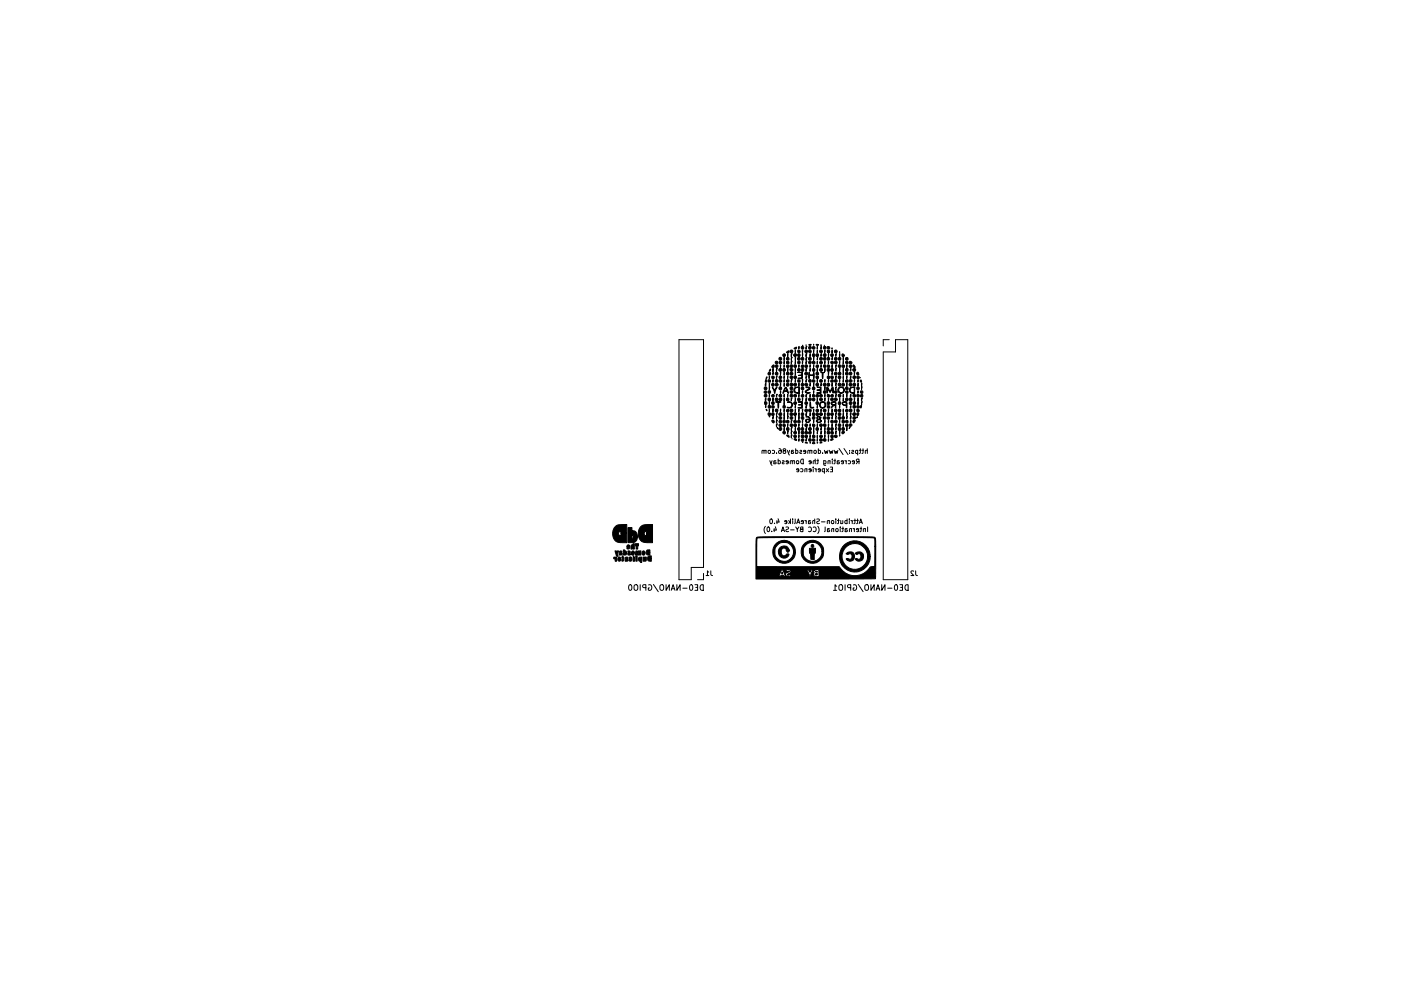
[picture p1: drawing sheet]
<svg xmlns="http://www.w3.org/2000/svg" width="297mm" height="210mm" viewBox="0 0 297 210" stroke-linecap="round" stroke-linejoin="round" font-family="sans-serif">
<g fill="none" stroke="#000" stroke-width=".21">
<path d="M144 72.1h5.2v48.3h-2.6v2.6h-2.6zM188.5 72.1h-1.2v1.3M189.9 72.1h2.6v50.9h-5.2v-48.3h2.6zM162 95.7l-.4-.1v.6M162.4 95.6h-.4v.6M162.4 95.5v.7M162.9 95.6h.4v.6l-.4-.1zM163.2 97.7l.5 1M163.7 97.7l-.2 .7M163.7 95.6l.3-.1 .2 .2-.1 .5h-.4M164.5 97.8l-.3-.1-.1 .2v.5h.3l.1-.3-.4-.1M164.6 96.1v.1"/>
<path d="M165 97.4v1h.4v-.6h-.4M165.2 95.2l.4 .2v.6l-.1 .2-.4-.1 .1-.5h.3l.1 .2M165.9 97.8l.4 .1-.4 .2v.3h.4M166.2 95.6l-.2 .2 .2 .4 .4-.1v-.3l-.5-.3v-.2h.5l-.2 .3M166.9 95.5l.5 1M167.1 98.1l-.5-.1 .1-.2 .3-.1 .1 .2v.5h-.4M167.4 95.5l-.2 .7M167.8 95.8l.5 .2-.2 .2h-.3M168 97.9l-.4-.1v.6M168.2 95.6h-.4v.6M168.4 97.8h-.4v.6M168.4 97.7v.7"/>
<path d="M168.7 95.6l.3-.1 .2 .2-.1 .5h-.4M168.7 95.2v1M168.9 97.8h.4v.6l-.4-.1zM169.4 99.8l-.5-.1v-.2l.3-.1 .2 .2-.1 .5h-.4M169.6 95.6l.4 .1-.4 .2v.3h.4M169.7 99.5l.3-.1 .2 .2-.1 .5h-.4M169.8 97.5l.5-.1v1a.52 .52 0 0 1-.5-.3 .52 .52 0 0 1 0-.6zM170.8 95.9l-.4-.1v-.2l.3-.1 .1 .2v.5h-.4M171.1 99.5h-.4l-.1 .6M171.1 99.4v.7M171.7 95.7l-.4-.1v.6M172 98.1l-.5-.1 .1-.2 .2-.1 .2 .2-.1 .5h-.3"/>
<path d="M172 99.8l-.5-.1 .1-.2 .2-.1 .2 .2-.1 .5h-.3M172.1 95.6h-.4v.6M172.1 95.5v.7M172.4 99.1v.1M172.4 99.4v.7M172.6 95.6h.4v.6l-.4-.1zM172.7 99.4l.3 .2M172.8 97.8h-.3l-.1 .6M172.8 97.4v1M173 99.4v.7M173.2 97.7h.4M173.4 97.4v.9l-.2 .1"/>
<path d="M173.5 95.6l.3-.1 .2 .2-.1 .5h-.4M173.5 95.2v1M173.9 99.8l-.4-.1v-.2l.3-.1 .1 .2v.5h-.4M174.4 96.1v.1M174.6 97.7v.8l.2 .2h.3M174.6 97.8l.3-.1 .2 .2-.1 .5h-.4M174.8 99.5l-.3-.1-.2 .2 .1 .5h.4M174.8 95.5l.2 .7 .2-.5 .2 .5 .2-.7M174.8 99.4v1M175.2 99.4l.5 .7M175.7 99.4l-.5 .7M175.8 95.5l.2 .7 .2-.5 .2 .5 .2-.7"/>
<path d="M176 97.8h-.4v.6M176 97.7v.7M176 99.1h.5v1h-.5M176.2 99.6h.3M176.5 97.4v.1M176.5 97.7v.7M176.8 97.7h.4M176.9 95.5l.2 .7 .2-.5 .2 .5 .1-.7M177 97.4v.9l-.2 .1M177.9 95.2l.8 1.2M177.9 97.8l-.3-.1-.1 .2v.5h.3l.1-.3-.4-.1M178.8 98.1l-.4-.1v-.2l.3-.1 .1 .2v.5h-.4"/>
<path d="M178.9 95.2l.9 1.2M179.1 97.7l.3 .2M179.4 97.7v.7M179.8 97.8l.3-.1 .2 .2-.1 .5h-.4M180.1 96.1v.1M180.1 95.6v.1M180.6 95.6l.4 .1-.4 .2v.3h.4M181.2 98.1l-.5-.1v-.2l.3-.1 .2 .2-.1 .5h-.4M181.8 95.6l-.2-.1-.2 .2 .1 .5h.3M181.8 95.5v1M181.9 97.9l-.3 .5M182.1 97.9h-.5v-.4l.5-.1v1"/>
<path d="M182.2 95.5h.4M182.4 95.2v.9l-.2 .1M182.7 95.5h.4M183 95.2v.9l-.3 .1M183.9 95.6h-.4v.6M183.9 95.2v1M162.3 111.7a1.15 1.15 0 0 0 0 1.5M162.7 111.9l.2-.1a.49 .49 0 0 1 .3 .5 .49 .49 0 0 1-.4 .5l-.2-.4zM163.4 110.2l.1-.1a.49 .49 0 0 1 .3 .5 .49 .49 0 0 1-.4 .5l-.2-.4zM163.6 112.7v.1M164.1 112.1v.7M164.2 111v.1"/>
<path d="M164.4 111.8l.2 .7h-.6M164.7 110.4v.7M165 110.1l.2 .7h-.6M165.7 112.8l.3-1 .3 1M165.8 112.5h.4M166.6 111.9h.5a.42 .42 0 0 1-.4 .5v.4h.5M166.8 110.8l-.4-.1v-.2l.3-.1 .1 .2v.5h-.4M167.2 110.4l.4 .4M167.5 110.7l-.3 .4M167.6 110.1v1M167.6 112.4h.8M168.1 110.1v.1"/>
<path d="M168.1 110.4v.7M168.6 110.1v.9l-.1 .1M168.7 111.8l.3 .5 .4-.5M168.9 111.1l.4-1 .3 1M169 110.8h.5M169 112.3v.5M169.9 112.3l-.2 .2 .2 .3h.3v-1l-.4 .1v.3l.4 .1M170.4 110.8l-.5-.1v-.2l.3-.1 .2 .2-.1 .5h-.4M170.6 110.4l.3 .2M170.9 110.4v.7M171.4 110.7l.5 .2-.2 .2h-.3M171.4 111.9a.44 .44 0 0 1 .7 .4 .44 .44 0 0 1-.7 .4"/>
<path d="M171.8 110.5h-.3l-.1 .6M172.4 111.9a.44 .44 0 0 1 .7 .4 .44 .44 0 0 1-.7 .4M172.7 110.5h-.3l-.1 .6M172.7 110.1v1M173.2 110.2h.5a.42 .42 0 0 1-.5 .5l.1 .4h.4M173.4 111.7a1.15 1.15 0 0 1 0 1.5M174.2 110.7h.7M175 111.8v.9l-.2 .1M175.4 112.4l.5 .2-.1 .2h-.4M175.8 110.5h-.3l-.1 .6M175.8 110.4v.7M175.9 112.2h-.4l-.1 .6"/>
<path d="M176.3 110.5h.4v.6l-.4-.1zM176.8 112.2h-.4l-.1 .6M176.8 112.1v.7M177.2 110.1v.1M177.2 110.4v.7M177.2 112.2h.5l-.1 .6-.4-.1zM177.5 110.4h.4M177.8 110.1v.9l-.3 .1M178.1 111.8v.1M178.1 112.1v.7M178.3 110.4v.7M178.5 112.1h.4"/>
<path d="M178.7 110.4l-.1 .7-.3-.1M178.7 111.8v.9l-.2 .1M179.2 112.4l.5 .2-.2 .2h-.3M179.6 110.5l-.3-.1-.2 .2 .1 .5h.4M179.6 110.1v1M179.6 112.2h-.4v.6M180.1 110.1v.1M180.1 110.4v.7M180.4 110.4l.3 .2M180.5 112.2h-.4v.6M180.5 112.1v.7M180.7 110.4v.7"/>
<path d="M180.9 112.1l.2 .2M181 110.4h.4M181.1 112.1v.7M181.3 110.1v.9l-.3 .1M181.6 110.4h.4M181.8 110.1v.9l-.2 .1M182 112.5l-.4-.1v-.2l.3-.1 .1 .2v.5h-.4M182.2 111.1l.3-1 .3 1M182.3 110.8h.4M182.3 112.1h.4M182.6 111.8v.9l-.3 .1M183.5 112.2h-.4l-.1 .6"/>
<path d="M183.5 112.1v.7M184 111.8v1M133.4 124.2l.2-.1a.64 .64 0 0 1 .4 .6 .64 .64 0 0 1-.4 .6l-.3-.5zM134.5 124.2l.2-.1a.4 .4 0 0 1 .5 .4v.4a.4 .4 0 0 1-.4 .4 .4 .4 0 0 1-.4-.4zM135.7 124.1v1.2M136.9 124.7l-.5-.1-.1-.4 .6-.1v1.2M137.5 124.1a.55 .55 0 0 1 .7 .6 .55 .55 0 0 1-.7 .4v-.4h.2M138.5 124l1.1 1.5M140 124.2l.2-.1a.4 .4 0 0 1 .5 .4v.4a.4 .4 0 0 1-.4 .4 .4 .4 0 0 1-.4-.4zM141.2 124.1v1.2l.7-1.2v1.2M142.3 125.3l.4-1.2 .4 1.2M142.4 124.9h.6"/>
<path d="M143.5 124.1v1.2l.7-1.2v1.2M144.8 124.8h.9M146.3 124.2l.2-.1a.64 .64 0 0 1 .4 .6 .64 .64 0 0 1-.4 .6l-.3-.5zM147.3 124.1h.6v1.2h-.6M147.5 124.6h.4M148.5 124.2l.6-.1v1.2a.63 .63 0 0 1-.6-.4 .63 .63 0 0 1 0-.7zM149.2 121.7v1.3h-1.3M149.7 122.1h.6M150.3 121.4l-.3-.3v1M150.7 121.1v.9l.4 .1M176.7 125.3h.7M177.4 124.4l-.3-.3v1.2"/>
<path d="M177.9 124.2l.2-.1a.4 .4 0 0 1 .6 .4v.4a.4 .4 0 0 1-.4 .4 .4 .4 0 0 1-.4-.4zM179.2 124.1v1.2M180.4 124.7l-.6-.1-.1-.4 .7-.1v1.2M180.9 124.1a.55 .55 0 0 1 .7 .6 .55 .55 0 0 1-.7 .4v-.4h.2M182 124l1 1.5M183.4 124.2l.2-.1a.4 .4 0 0 1 .5 .4v.4a.4 .4 0 0 1-.4 .4 .4 .4 0 0 1-.4-.4zM184.7 124.1v1.2l.6-1.2v1.2M185.7 125.3l.4-1.2 .4 1.2M185.9 124.9h.5M186.9 124.1v1.2l.7-1.2v1.2M188.2 124.8h.9M189.7 124.2l.2-.1a.64 .64 0 0 1 .4 .6 .64 .64 0 0 1-.4 .6l-.3-.5z"/>
<path d="M190.8 124.1h.5v1.2h-.5M190.9 124.6h.4M192 124.2l.5-.1v1.2a.63 .63 0 0 1-.6-.4 .63 .63 0 0 1 .1-.7zM193.7 121.2l-.4-.1-.2 .3 .7 .7h-.7M194.1 121.1l.1 .9 .3 .1"/>
</g>
<g fill="#000" stroke="#000" stroke-width=".21">
<path d="M162.6 80l-.2 .3zM163.1 79.8v.5zM163.3 78.4l.1-.1v.3l-.3 .2zM163.9 78.2v.7zM163.9 79v.5zM163.8 77.5l.3-.1v.5h-.5zM164.6 79.8h.2l-.2 .5zM164.6 78.2h.2l-.2 .6zM165.5 77.4v.6zM165.5 78.9v.7zM166.3 79.8l-.1 .5zM166.3 77.4l-.1 .6z"/>
<path d="M166.3 76.6l-.1 .6zM166.2 78.9v.7zM166.2 75.8v.7zM166.8 75.9h.4v.5l-.4-.1zM166.8 77.5h.4v.4l-.5-.1zM167 79.8v.5zM167 78.2v.7zM167 75v.7zM166.8 74.7l.5-.3-.1 .4h-.3zM167.8 76.7l.2-.1-.2 .6zM167.8 75h.2l-.2 .7zM167.9 75.8h.1l-.2 .7z"/>
<path d="M168.6 76.6v.6zM168.6 74.2v.6zM168.6 78.1v.7zM168.6 78.9v.7zM168.6 75.8v.7zM168.4 73.9l.5-.2a.31 .31 0 0 1-.2 .3 .31 .31 0 0 1-.4-.1zM169.1 79h1v1.3h-.9l.7-.2 .1-.4-.7-.1 .5-.1 .2-.3zM169.2 76.7l.4 .1-.1 .4-.4-.1zM169.4 77.4v.6zM169.4 73.5v.6zM170 75.9h.4l-.1 .5-.4-.1zM170 77.5h.3v.4l-.4-.1z"/>
<path d="M170.2 76.6l-.1 .6zM170.2 74.2l-.1 .6zM170.1 73.3h.1zM170.1 75v.7zM170.9 73.2v.1zM170.9 79.8h.2l-.2 .5zM170.9 76.7l.2-.1-.2 .6zM170.9 73.5h.2l-.2 .6zM170.9 78.2h.2l-.2 .6zM170.9 75h.2l-.2 .7zM171 75.8h.1l-.2 .7zM171.6 79a.5 .5 0 0 0 .4 .5 .5 .5 0 0 0 .6-.5v1.3l-.1-.6h-.9l-.1 .6z"/>
<path d="M171.5 73.1h.5l-.2 .2zM171.8 77.4l-.1 .6zM171.8 78.1l-.1 .7zM171.8 75l-.1 .7zM172.5 77.4v.6zM172.5 74.2v.6zM172.5 73v.3zM172.5 75.8v.7zM173 73.1l.6 .1-.4 .1zM173.1 77.5h.4v.4l-.5-.1zM173.3 76.6v.6zM173.3 74.2v.6z"/>
<path d="M173.3 73.5v.6zM173.3 78.2v.7zM173.3 75.8v.6zM174 73.2l.2 .1zM174 77.5h.2l-.1 .5zM174 73.6h.2l-.1 .5zM174 75.1l.1-.1 .1 .2-.2 .4zM174 79h.8l-.3 .1-.1 1.2-.1-1.2zM174.9 76.6v.6zM174.9 74.2v.6zM174.9 78.2v.7zM175.7 76.6l-.1 .6z"/>
<path d="M175.6 78.9v.7zM175.6 75v.7zM176.4 73.8v.2zM176.4 77.4v.6zM176.4 74.3v.6zM176.5 79l-.1 .5zM176.5 75.8l-.1 .6zM177.2 78.2h.1l-.1 .5zM177.2 75.1l.1-.1-.1 .6zM177.3 79.8l-.1 .5zM177.3 77.4l-.1 .6zM178 76.6v.6z"/>
<path d="M178 75v.7zM178 74.6v.2zM178 78.2v.7zM178.8 79.8v.5zM178.8 76.6v.6zM178.8 78.9v.7zM178.8 78.2v.7zM178.8 75.8v.7zM179.6 79.8l-.1 .5zM179.5 77.4v.6zM180.4 79.8l-.1 .5zM180.4 78.2l-.1 .5z"/>
<path d="M180.9 77.4l.5 .5h-.4zM181.1 78.9v.7zM181.8 79l.2 .2 .1 .3-.1 .1-.3-.2zM162.3 86.1l.1-.1-.1 .5zM162.3 84.5v.5zM162.3 81.3v.6zM162.4 80.5l.2 .2v.2l-.2 .2-.2-.1zM162.4 86.8l.2 .4zM162.9 86.1l.5 .1-.1 .4-.4-.1zM162.9 83h.5l-.1 .4h-.4zM163.1 88.4h.1zM163.1 86.8v.6z"/>
<path d="M163.1 83.6v.6zM163.1 85.2v.7zM163.1 82.1v.7zM163.1 81.3v.7zM163.6 89.2h.5v.4l-.2 .1zM163.7 85.3h.4v.5l-.5-.1zM163.7 83.8l.4-.1v.5l-.5-.1zM163.9 80.5v.6zM163.9 86.8v.6zM163.9 84.4v.7zM163.9 88.4v.5zM163.8 82.1l.4 .7 .4-.6h.2l-.5 1.3z"/>
<path d="M164.6 90l.2-.1-.2 .6zM164.6 89.2h.2l-.2 .5zM164.6 83.7h.2l-.2 .5zM164.7 88.3l.1 .1-.2 .6zM164.7 87.6h.1l-.1 .7zM164.4 85.3h1.2h-.5l-.1 1.3-.1-1.3zM164.7 90.7l.3 .3zM165.5 86.8v.6zM165.5 82.9v.6zM165.5 81.3v.7zM166 89.2l.5 .1-.1 .4-.4-.1zM166 86.1l.5 .1-.1 .4-.4-.1z"/>
<path d="M166.3 86.8l-.1 .6zM166.3 83.6l-.1 .6zM166.3 80.5l-.1 .6zM166.2 90.7v.7zM166.2 88.3v.7zM166.2 87.6v.7zM166.2 85.2v.7zM166.2 84.4v.7zM166.2 81.3v.7zM166.5 82.2l-.1 .6 .4 .1-.2-.7 .5 1.3a.6 .6 0 0 0-.5-.4 .6 .6 0 0 0-.6 .4zM166.8 92.3l.4 .1 .1 .4-.4-.3zM166.8 86.9h.4v.4l-.5-.1z"/>
<path d="M166.8 80.6h.4v.5l-.5-.1zM167 89.9v.6zM167 83.6v.6zM167 87.6v.7zM166.9 85.3a.69 .69 0 0 1 1 .1 .69 .69 0 0 1-.1 1 .69 .69 0 0 1-.9 0 .61 .61 0 0 0 1-.4 .61 .61 0 0 0-.9-.6zM167.1 91.5l-.1 .5zM167.1 88.4l-.1 .5zM167.8 92.3h.2l-.2 .6zM167.8 89.2h.2l-.2 .5zM167.8 80.6l.2-.1-.2 .6zM167.8 84.4h.2l-.2 .7zM167.9 91.4l.1 .1-.2 .7z"/>
<path d="M167.8 90.7h.2l-.2 .7zM168.4 93.1h.3l.2 .3h-.4zM168.6 86.8v.6zM168.6 86v.6zM168.6 80.5v.6zM168.6 90.7v.6zM168.6 84.4v.7zM168.6 88.3v.7zM168.5 82.3l.6-.2 .4 .1a.63 .63 0 0 0-.9 .2 .63 .63 0 0 0 .2 .9h.5v-1.1h.2v1.3h-.4a.69 .69 0 0 1-.7-.4 .69 .69 0 0 1 .1-.8zM169.4 93v.6zM169.4 92.3v.6zM169.4 89.9v.6z"/>
<path d="M169.4 86.8v.6zM169.4 83.6v.6zM169.4 91.5v.7zM169.4 88.3v.7zM169.4 87.6v.7zM169.4 81.3v.7zM169.2 85.3l.9-.1v1.4l-.9-.1 .7-.1 .1-.2-.1-.3h-.6l.7-.2v-.3zM170 91.5l.4 .1-.1 .5-.4-.1zM170 93.2l.3-.1v.5l-.4-.1zM170 83.8l.3-.1v.5l-.4-.1zM170.2 89.1l-.1 .6zM170.2 82.9l-.1 .6z"/>
<path d="M170.1 93.8l.1 .1zM170.1 89.9v.6zM170.1 86.8v.6zM170.1 80.5v.6zM170.1 84.4v.7zM170.7 93.9l.5 .1zM170.9 93.1h.2l-.2 .5zM170.9 86.1l.2-.1-.2 .6zM170.9 83.7h.2l-.2 .5zM170.9 80.6l.2-.1-.2 .6zM170.9 84.4h.2l-.2 .7zM170.9 90.7h.2l-.2 .7z"/>
<path d="M170.9 87.6h.2l-.2 .7zM170.9 82.2l.3-.1 .5 .2-.1 .3-.7 .5 .2 .2h.7l-.7 .1-.4-.2 .2-.3 .7-.6zM170.9 88.4a.63 .63 0 0 1 .7 .1 .63 .63 0 0 1 .2 .7l-.7-.2-.1 .4 .4 .1 .2-.3h.2a.5 .5 0 0 1-.5 .5 .5 .5 0 0 1-.5-.4l.2-.4 .6-.1a.54 .54 0 0 0-.7-.3zM171.8 93.8v.2zM171.8 92.3l-.1 .6zM171.8 89.9l-.1 .6zM171.8 83.6l-.1 .6zM171.8 81.3l-.1 .7zM171.7 87.6v.7zM171.8 85.3l.2 1.1h.5l-.3 .2a.9 .9 0 0 1-.4-1.3zM172.3 93.9h.4l.1 .2h-.5zM172.5 89.1v.6z"/>
<path d="M172.5 86.8v.6zM172.5 82.9v.6zM172.5 91.5v.7zM172.5 90.7v.7zM172.5 81.3v.7zM173.1 85.3h.4v.5l-.5-.1zM173.1 86.9h.4v.4l-.5-.1zM173.1 83.8l.4-.1v.5l-.5-.1zM173.3 93.8v.2zM173.3 93v.6zM173.3 92.3v.6zM173.3 86v.6z"/>
<path d="M173.3 89.9v.6zM173.3 80.5v.6zM173.3 84.4v.7zM173.3 91.5v.5zM173.3 88.5a.52 .52 0 0 1 .7 .1l-.5-.1-.2 .2 .3 .2 .4-.3-.1 .4 .2 .3-.1-.1a.34 .34 0 0 0-.5-.1 .34 .34 0 0 0-.2 .4h.4l.4-.2a.55 .55 0 0 1-.5 .4 .55 .55 0 0 1-.5-.4l.2-.3zM173.2 82.2l.9-.1v1.4l-1-.1a.62 .62 0 0 0 .8-.4l-.1-.2h-.6l.7-.2a.45 .45 0 0 0-.2-.4 .45 .45 0 0 0-.5 0zM173.9 93.9h.4l-.4 .1zM174 86.9h.2l-.1 .5zM174 90.7h.1l.1 .1-.2 .5zM174 81.3h.1l.1 .1-.2 .5zM173.8 85.5a.69 .69 0 0 1 .8-.3 .69 .69 0 0 1 .5 .7h-.2a.51 .51 0 0 0-.6-.4 .51 .51 0 0 0-.3 .7 .51 .51 0 0 0 .7 .1l.2-.4h.2a.7 .7 0 0 1-.9 .7 .7 .7 0 0 1-.4-1.1zM174.1 91.5l.1 .1-.1 .5z"/>
<path d="M174.9 92.3v.6zM174.9 89.1v.6zM174.9 83.6v.6zM174.9 80.5v.6zM174.9 90.7v.6zM174.9 91.5v.7zM174.9 87.6v.7zM174.9 84.4v.7zM174.9 82.1v.7zM175.7 93l-.1 .6zM175.7 92.3l-.1 .6zM175.7 89.9l-.1 .6z"/>
<path d="M175.7 89.1l-.1 .6zM175.7 86.8l-.1 .6zM175.7 80.5l-.1 .6zM175.6 84.4v.7zM176.2 83.8l.4-.1v.5l-.5-.1zM176.2 80.6h.4v.5l-.5-.1zM176.2 93.2l.3-.1h.2l-.5 .3zM176.4 89.9v.6zM176.4 86.8v.6zM176.4 81.3v.7zM175.3 82.1l.3 .2 .4 .8 .4-.9h.2v1.2l-.1-1.1-.5 1-.6-1.1v1.2zM176.5 88.4l-.1 .5z"/>
<path d="M176.3 85.3l.8-.1 .1 .4a.47 .47 0 0 0-.8 0 .48 .48 0 0 0 .8 0v1l-.1-.6h-.2l-.7 .6 .4-.6-.3-.2zM177.3 88.3l.1 .1-.2 .6zM177.3 82.1h.1l-.2 .6zM177.2 90.7h.1l-.1 .6zM177.2 87.6h.2l-.2 .6zM177.3 91.5l-.1 .6zM177.3 89.9l-.1 .6zM177.3 83.7l-.1 .5zM177.3 81.3l-.1 .6zM178 92.3h.1l-.1 .2zM178 89.1v.6zM178 86v.6z"/>
<path d="M178 80.5v.6zM178 91.5v.7zM178 84.4v.7zM177.8 82.3l.8-.2 .4 .4 .1 .2h-.2a.53 .53 0 0 0-.8-.4 .53 .53 0 0 0-.1 .9 .53 .53 0 0 0 .8-.2l.1-.3h.2a.72 .72 0 0 1-1 .7 .72 .72 0 0 1-.3-1.1zM178.6 91.6l.3-.1 .1 .3-.4 .2zM178.8 89.9v.6zM178.8 86.8v.6zM178.8 83.6v.6zM178.8 80.5v.6zM178.8 87.6v.7zM178.8 84.4v.7zM178.6 85.4l.8-.2 .2 .4h-.2a.37 .37 0 0 0-.4-.3 .37 .37 0 0 0-.3 .4l.5 .2 .4-.3-.1 1-.2-.6a.6 .6 0 0 1-.7-.4z"/>
<path d="M179.4 90h.3v.5l-.4-.1zM179.4 86.9h.3v.4l-.4-.1zM179.4 80.6h.3v.5l-.4-.1zM179.5 83.7v.6zM179.5 90.7v.7zM179.5 87.6v.7zM179.5 81.3v.7zM179.6 88.4v.5zM180 90.9l.3-.2zM180.3 87.6l.1-.1 .1 .2-.2 .5zM180.4 88.3l-.1 .7zM180.4 89.2l-.1 .5z"/>
<path d="M180.4 86l-.1 .6zM180.4 83.7l-.1 .5zM180.2 82.3l.6-.2 .4 .1a.62 .62 0 0 0-.9 .5 .62 .62 0 0 0 .8 .6v-1.1h.1v1.2a.74 .74 0 0 1-.9-.2 .74 .74 0 0 1-.1-.9zM180.9 89.2h.4l-.3 .5-.2-.3zM181.2 86.8l-.1 .6zM181.2 80.5l-.1 .6zM181.1 84.4v.7zM181.7 88.5l.1-.1-.2 .3zM181.9 82.9v.6zM181.9 80.5v.6zM181.7 87.7l.3-.1-.1 .6-.2-.2zM181.9 85.2v.7z"/>
<path d="M181.9 84.4v.7zM181.9 81.3v.7zM182.4 80.7h.2l.1 .4-.3-.1zM182.5 86.1h.2l-.2 .5zM182.5 83.8l.4-.1v.5l-.5-.1zM182.7 81.3v.7zM182.7 84.4h.2l-.2 .7zM182.8 85.2v.1l-.1 .6zM182.7 82.1v.5zM130.4 116.9h.3l.1 .2 .3-.2-.2 .7 .2 .4h-.4zM130.1 118.3l.6-.1v.9h-.3v-.5a.21 .21 0 0 1-.3-.1 .21 .21 0 0 1 0-.2zM131.1 118.3l.3-.1 .2 .2v.2l-.3-.1-.1 .2 .4-.1a.37 .37 0 0 1-.5 .4 .37 .37 0 0 1-.1-.6z"/>
<path d="M131.3 117a.28 .28 0 0 1 .4-.1 .28 .28 0 0 1 .2 .3l-.3 .1 .3 .2h-.3h.3v.2l-.6 .1zM132 117.9l.3 .5a.44 .44 0 0 1-.4 .7l-.1-.8zM130.5 111.7a1.75 1.75 0 0 1 1.5-.4h.9v1.8h-1.2l-.1-.3a.39 .39 0 0 0-.5 .4 .39 .39 0 0 0 .5 .3l.1-.4h1.2v2a3.1 3.1 0 0 1-2.6-.5 2.32 2.32 0 0 1 .2-2.9zM132.2 116.7h.2l.1 .2 .3 .2 .1 .3-.4-.2v.3l.4-.1-.2 .3-.5 .1zM132.7 118.2a.29 .29 0 0 1 .3 0 .29 .29 0 0 1 .2 .3h-.3l.3 .3h-.3h.3l-.1 .2-.6 .1zM133 115.7l.3-.1 .2 .2-.4 .1h.4a.35 .35 0 0 1-.1 .5 .35 .35 0 0 1-.5-.2h.3l-.3-.2zM133.1 116.9a.33 .33 0 0 1 .5 .1 .33 .33 0 0 1-.2 .5h.2a.3 .3 0 0 1-.3 .3 .3 .3 0 0 1-.3-.3 .3 .3 0 0 1 .4-.3zM133.5 118.2a.42 .42 0 0 1 .5 .4 .42 .42 0 0 1-.5 .4l-.1-.3 .2-.1a.21 .21 0 0 1-.2-.2 .21 .21 0 0 1 .1-.2zM133.1 111.9h.9v.8a.95 .95 0 0 1 1.1 1.2h-.8l-.2-.3-.1 .6h.2l.1-.3h.8a1.18 1.18 0 0 1-1.4 1.2h-.6zM134.1 116.9h.2l.2 .3-.4-.1v.1h.4a.35 .35 0 0 1-.1 .5 .35 .35 0 0 1-.5-.2l.3-.1h-.3zM134.2 118.2h.3v.9h-.3zM133.8 115.7h.4v-.3h.3v1.1h-.3l-.1-.6-.1 .6h-.2z"/>
<path d="M134.3 118h.1l-.1 .1zM134.7 115.4h.7l-.2 1.1h-.3zM134.8 117.9h.3v1.2h-.3zM134.9 116.9l.3 .1 .7-.1v.9h-.3l-.1-.7-.1 .7h-.2l-.1-.7-.1 .7h-.3zM135.5 118.3l.6-.1v.5l-.4-.2v.2v.1l.4-.1v.6h-.3v-.2a.5 .5 0 0 1-.4-.3 .5 .5 0 0 1 .1-.5zM136.3 116.9l.3 .1 .2 .3-.4-.1v.2l.4-.1v.2a.37 .37 0 0 1-.6 .2 .37 .37 0 0 1 0-.6zM136.3 118.2h.4v.6l.1-.6h.2l-.1 .8-.5 .1zM137.1 116.8l.7-.1v.5l-.4-.1-.1 .1 .1 .1 .4-.1v.6a.6 .6 0 0 1-.8-.3 .6 .6 0 0 1 .1-.7zM135.9 111.7a2.99 2.99 0 0 1 2.4-.4v2.4h-1.2l-.1-.8a.42 .42 0 0 0-.4 .4 .42 .42 0 0 0 .5 .4h1.2v1.4a3.2 3.2 0 0 1-2.5-.4 2.39 2.39 0 0 1 .1-3zM137.4 118.1l.7-.2v.6h-.3l-.1-.1-.1 .1 .1 .2 .1-.2h.3v.6h-.4a.58 .58 0 0 1-.3-1zM164.6 115.3a2.41 2.41 0 0 1 2.7-.4 2.41 2.41 0 0 1 1.3 2.3h-.3a2.02 2.02 0 0 0-2.8-2 2.02 2.02 0 0 0-.7 3.3 2.02 2.02 0 0 0 3.3-.8l.2-.5h.3a2.42 2.42 0 0 1-3.4 2.1 2.42 2.42 0 0 1-.6-4zM165.4 116.2a1.16 1.16 0 0 1 1.2-.3 1.16 1.16 0 0 1 .8 1l-.4 .3-.3-.5a.48 .48 0 0 0-.7-.4 .94 .94 0 0 0 .2 1.6l.4-.1 .2-.3 .5 .1a1.12 1.12 0 0 1-1.2 .8 1.12 1.12 0 0 1-1-1.1l-.1-.4z"/>
<path d="M160.4 114l3.8-.1h20.9l.3 .1 .2 .2 .1 1.7h-.2v-1.4a.46 .46 0 0 0-.3-.5 .46 .46 0 0 0-.5 .1h-24.1a2.21 2.21 0 0 0-.2 1.7v4.4h17.5a3.8 3.8 0 0 0 6.6 .1l1-.1v-4.3h.2l-.1 6.4h-11.9l-.1-1.3-.3-.2h-1.1l-.5 .6-.3-.5h-.3l.4 1.1h-3.8l-.1-.2-.6 .2v-.2l.6-.3a.46 .46 0 0 0-.3-.7 .46 .46 0 0 0-.6 .5l.5-.1h.2a.81 .81 0 0 0-.8 .8l.4 .3h-.5l-.7-1.4-.4 .6-.2 .7 .1 .1a.61 .61 0 0 1 .5-.3 .61 .61 0 0 1 .6 .3h.8l.5-.3h3.8l.3 .3 .6-1.4h.5l-.4 .3 .1 .3a.54 .54 0 0 0 0 .7 .54 .54 0 0 0 .7 .1h12.3v.5h-.4h-24.9v-7.7zM171.6 116.3h1.3l-.3 2.4h-.7zM170.5 115.4a2.36 2.36 0 0 1 2.6-.6 2.36 2.36 0 0 1 1.5 2.2h-.3a1.99 1.99 0 0 0-3-1.7 1.99 1.99 0 0 0-.2 3.4 1.99 1.99 0 0 0 3.1-1.2l.1-.5h.3a2.42 2.42 0 0 1-3.3 2.4 2.42 2.42 0 0 1-.8-4zM179.4 117.5a.98 .98 0 0 1 1.4-.2 .98 .98 0 0 1 .1 1.4 .98 .98 0 0 1-1.5-.1l.4-.1a.56 .56 0 0 0 .7-.1 .56 .56 0 0 0 0-.7 .56 .56 0 0 0-.8-.1zM179.1 115.5a3.3 3.3 0 0 1 3.6-.4 3.3 3.3 0 0 1 1.8 3h-.5a2.72 2.72 0 0 0-3.9-2.5 2.72 2.72 0 0 0-.6 4.5 2.72 2.72 0 0 0 4.4-1.4l.1-.6h.5a3.3 3.3 0 0 1-4.7 2.9 3.3 3.3 0 0 1-.7-5.5zM181.4 117.3a.98 .98 0 0 1 1.4 0 .98 .98 0 0 1 0 1.4 .98 .98 0 0 1-1.4-.1l.2-.1a.6 .6 0 0 0 1-.2 .6 .6 0 0 0-.5-.9l-.4 .2-.3-.1zM165.8 121.3l.1 .3-.1 .1zM172.9 121.2l.4 .1-.2 .1zM172.9 121.7h.4v.2l-.5 .1z"/>
<circle cx="163.1" cy="79.3" r=".3"/>
<circle cx="164.7" cy="77.7" r=".3"/>
<circle cx="164.7" cy="79.3" r=".31"/>
<circle cx="164.7" cy="76.9" r=".3"/>
<circle cx="165.4" cy="78.5" r=".3"/>
<circle cx="165.4" cy="76.1" r=".31"/>
<circle cx="165.5" cy="76.9" r=".3"/>
<circle cx="166.2" cy="78.5" r=".3"/>
<circle cx="166.2" cy="75.4" r=".29"/>
<circle cx="167" cy="79.3" r=".3"/>
<circle cx="167" cy="76.9" r=".3"/>
<circle cx="167.8" cy="77.7" r=".3"/>
<circle cx="167.8" cy="79.3" r=".32"/>
<circle cx="167.8" cy="74.6" r=".31"/>
<circle cx="167.8" cy="78.5" r=".34"/>
<circle cx="168.6" cy="75.3" r=".3"/>
<circle cx="168.6" cy="77.7" r=".3"/>
<circle cx="169.4" cy="75.3" r=".3"/>
<circle cx="169.4" cy="78.5" r=".3"/>
<circle cx="169.4" cy="76.1" r=".3"/>
<circle cx="169.4" cy="74.5" r=".3"/>
<circle cx="170.1" cy="78.5" r=".31"/>
<circle cx="170.1" cy="73.8" r=".31"/>
<circle cx="170.9" cy="79.3" r=".31"/>
<circle cx="170.9" cy="74.6" r=".3"/>
<circle cx="170.9" cy="77.7" r=".31"/>
<circle cx="171.7" cy="76.1" r=".31"/>
<circle cx="171.7" cy="73.8" r=".3"/>
<circle cx="171.7" cy="76.9" r=".3"/>
<circle cx="171.7" cy="74.5" r=".3"/>
<circle cx="172.5" cy="75.3" r=".3"/>
<circle cx="172.5" cy="78.5" r=".3"/>
<circle cx="172.5" cy="73.8" r=".3"/>
<circle cx="172.5" cy="76.9" r=".3"/>
<circle cx="173.3" cy="75.4" r=".31"/>
<circle cx="173.3" cy="79.3" r=".3"/>
<circle cx="174.1" cy="76.1" r=".31"/>
<circle cx="174.1" cy="74.6" r=".31"/>
<circle cx="174.1" cy="78.5" r=".31"/>
<circle cx="174.1" cy="76.9" r=".3"/>
<circle cx="174.9" cy="73.8" r=".3"/>
<circle cx="174.9" cy="75.3" r=".31"/>
<circle cx="174.9" cy="77.7" r=".3"/>
<circle cx="174.9" cy="76.1" r=".3"/>
<circle cx="175.6" cy="78.5" r=".3"/>
<circle cx="175.6" cy="76.1" r=".3"/>
<circle cx="175.6" cy="73.8" r=".3"/>
<circle cx="175.7" cy="74.5" r=".3"/>
<circle cx="175.7" cy="77.7" r=".3"/>
<circle cx="176.4" cy="75.4" r=".31"/>
<circle cx="176.4" cy="78.5" r=".31"/>
<circle cx="176.4" cy="76.9" r=".28"/>
<circle cx="177.2" cy="79.3" r=".31"/>
<circle cx="177.2" cy="76.9" r=".29"/>
<circle cx="177.2" cy="76.1" r=".31"/>
<circle cx="177.2" cy="74.6" r=".31"/>
<circle cx="178" cy="77.7" r=".3"/>
<circle cx="178" cy="79.3" r=".3"/>
<circle cx="178" cy="76.1" r=".3"/>
<circle cx="178.8" cy="75.4" r=".31"/>
<circle cx="178.8" cy="77.7" r=".3"/>
<circle cx="179.5" cy="79.3" r=".3"/>
<circle cx="179.5" cy="76.1" r=".3"/>
<circle cx="179.5" cy="78.5" r=".31"/>
<circle cx="179.5" cy="76.9" r=".28"/>
<circle cx="180.3" cy="79.3" r=".3"/>
<circle cx="180.4" cy="76.9" r=".31"/>
<circle cx="180.4" cy="77.7" r=".31"/>
<circle cx="181.1" cy="78.5" r=".31"/>
<circle cx="162.3" cy="82.4" r=".31"/>
<circle cx="162.3" cy="84" r=".31"/>
<circle cx="162.3" cy="83.2" r=".3"/>
<circle cx="162.3" cy="85.5" r=".32"/>
<circle cx="163.1" cy="84.8" r=".32"/>
<circle cx="163.1" cy="87.8" r=".3"/>
<circle cx="163.1" cy="80.8" r=".31"/>
<circle cx="163.9" cy="81.6" r=".3"/>
<circle cx="163.9" cy="87.9" r=".3"/>
<circle cx="163.9" cy="80" r=".3"/>
<circle cx="163.9" cy="86.3" r=".3"/>
<circle cx="164.7" cy="84.8" r=".31"/>
<circle cx="164.7" cy="87.1" r=".3"/>
<circle cx="164.7" cy="80.8" r=".29"/>
<circle cx="164.7" cy="81.6" r=".33"/>
<circle cx="165.4" cy="82.4" r=".31"/>
<circle cx="165.4" cy="88.7" r=".31"/>
<circle cx="165.5" cy="90.2" r=".31"/>
<circle cx="165.5" cy="80.8" r=".31"/>
<circle cx="165.5" cy="84" r=".31"/>
<circle cx="165.5" cy="91" r=".31"/>
<circle cx="165.5" cy="84.7" r=".31"/>
<circle cx="165.5" cy="87.9" r=".31"/>
<circle cx="165.5" cy="89.4" r=".3"/>
<circle cx="165.5" cy="80" r=".3"/>
<circle cx="166.3" cy="90.2" r=".3"/>
<circle cx="166.3" cy="91.8" r=".28"/>
<circle cx="167" cy="81.6" r=".3"/>
<circle cx="167" cy="84.7" r=".3"/>
<circle cx="167" cy="89.4" r=".3"/>
<circle cx="167" cy="91" r=".32"/>
<circle cx="167.8" cy="80" r=".3"/>
<circle cx="167.8" cy="88.7" r=".3"/>
<circle cx="167.8" cy="83.2" r=".29"/>
<circle cx="167.8" cy="82.4" r=".31"/>
<circle cx="167.8" cy="87.1" r=".31"/>
<circle cx="167.8" cy="84" r=".31"/>
<circle cx="167.8" cy="90.2" r=".31"/>
<circle cx="167.8" cy="81.6" r=".34"/>
<circle cx="167.8" cy="87.9" r=".33"/>
<circle cx="168.6" cy="90.2" r=".31"/>
<circle cx="168.6" cy="84" r=".31"/>
<circle cx="168.6" cy="85.5" r=".3"/>
<circle cx="168.6" cy="91.8" r=".3"/>
<circle cx="168.6" cy="80" r=".3"/>
<circle cx="168.6" cy="81.6" r=".3"/>
<circle cx="168.6" cy="92.6" r=".31"/>
<circle cx="168.6" cy="89.4" r=".31"/>
<circle cx="168.6" cy="87.9" r=".31"/>
<circle cx="169.4" cy="91" r=".3"/>
<circle cx="169.4" cy="84.7" r=".3"/>
<circle cx="169.4" cy="80.8" r=".3"/>
<circle cx="169.4" cy="89.4" r=".3"/>
<circle cx="170.1" cy="91" r=".3"/>
<circle cx="170.1" cy="81.6" r=".3"/>
<circle cx="170.1" cy="87.9" r=".3"/>
<circle cx="170.1" cy="88.7" r=".3"/>
<circle cx="170.1" cy="82.4" r=".3"/>
<circle cx="170.1" cy="92.6" r=".31"/>
<circle cx="170.9" cy="87.1" r=".3"/>
<circle cx="170.9" cy="92.6" r=".29"/>
<circle cx="170.9" cy="85.5" r=".32"/>
<circle cx="170.9" cy="91.8" r=".32"/>
<circle cx="170.9" cy="90.2" r=".31"/>
<circle cx="170.9" cy="81.6" r=".34"/>
<circle cx="171.7" cy="91.8" r=".3"/>
<circle cx="171.7" cy="91" r=".32"/>
<circle cx="171.7" cy="84.7" r=".31"/>
<circle cx="171.7" cy="93.3" r=".3"/>
<circle cx="171.7" cy="80.8" r=".3"/>
<circle cx="171.7" cy="87.1" r=".3"/>
<circle cx="172.5" cy="84.7" r=".3"/>
<circle cx="172.5" cy="87.9" r=".3"/>
<circle cx="172.5" cy="88.7" r=".3"/>
<circle cx="172.5" cy="82.4" r=".3"/>
<circle cx="172.5" cy="90.2" r=".31"/>
<circle cx="172.5" cy="80.8" r=".31"/>
<circle cx="172.5" cy="93.3" r=".31"/>
<circle cx="172.5" cy="83.9" r=".31"/>
<circle cx="172.5" cy="92.6" r=".3"/>
<circle cx="173.3" cy="81.6" r=".31"/>
<circle cx="173.3" cy="91" r=".3"/>
<circle cx="173.3" cy="87.9" r=".3"/>
<circle cx="173.3" cy="80" r=".31"/>
<circle cx="174.1" cy="93.3" r=".31"/>
<circle cx="174.1" cy="84" r=".31"/>
<circle cx="174.1" cy="80.8" r=".31"/>
<circle cx="174.1" cy="90.2" r=".31"/>
<circle cx="174.1" cy="87.9" r=".31"/>
<circle cx="174.1" cy="84.7" r=".31"/>
<circle cx="174.1" cy="92.6" r=".3"/>
<circle cx="174.8" cy="87.1" r=".31"/>
<circle cx="174.9" cy="83.2" r=".3"/>
<circle cx="174.9" cy="88.7" r=".3"/>
<circle cx="174.9" cy="81.6" r=".31"/>
<circle cx="174.9" cy="93.3" r=".3"/>
<circle cx="174.9" cy="90.2" r=".3"/>
<circle cx="175.6" cy="91.8" r=".3"/>
<circle cx="175.6" cy="91" r=".3"/>
<circle cx="175.6" cy="81.6" r=".3"/>
<circle cx="175.6" cy="87.9" r=".3"/>
<circle cx="175.6" cy="85.5" r=".3"/>
<circle cx="175.6" cy="88.7" r=".29"/>
<circle cx="175.7" cy="83.9" r=".3"/>
<circle cx="175.7" cy="80" r=".3"/>
<circle cx="175.7" cy="86.3" r=".3"/>
<circle cx="176.4" cy="91" r=".31"/>
<circle cx="176.4" cy="87.9" r=".31"/>
<circle cx="176.4" cy="84.8" r=".31"/>
<circle cx="176.4" cy="91.8" r=".3"/>
<circle cx="176.4" cy="80" r=".31"/>
<circle cx="176.4" cy="92.6" r=".3"/>
<circle cx="176.4" cy="89.4" r=".3"/>
<circle cx="177.2" cy="92.6" r=".29"/>
<circle cx="177.2" cy="83.2" r=".29"/>
<circle cx="177.2" cy="89.5" r=".29"/>
<circle cx="177.2" cy="87.1" r=".31"/>
<circle cx="177.2" cy="80.8" r=".31"/>
<circle cx="177.2" cy="84.7" r=".34"/>
<circle cx="178" cy="87.9" r=".31"/>
<circle cx="178" cy="80" r=".3"/>
<circle cx="178" cy="91" r=".32"/>
<circle cx="178" cy="81.6" r=".32"/>
<circle cx="178" cy="85.5" r=".31"/>
<circle cx="178" cy="83.9" r=".3"/>
<circle cx="178" cy="90.2" r=".3"/>
<circle cx="178" cy="88.7" r=".3"/>
<circle cx="178" cy="87.1" r=".29"/>
<circle cx="178.8" cy="91" r=".3"/>
<circle cx="178.8" cy="81.6" r=".3"/>
<circle cx="178.8" cy="88.7" r=".3"/>
<circle cx="178.8" cy="89.4" r=".3"/>
<circle cx="179.5" cy="84.8" r=".31"/>
<circle cx="179.5" cy="82.4" r=".3"/>
<circle cx="179.5" cy="83.2" r=".28"/>
<circle cx="179.6" cy="89.4" r=".3"/>
<circle cx="180.3" cy="85.5" r=".31"/>
<circle cx="180.3" cy="87.1" r=".31"/>
<circle cx="180.3" cy="90.2" r=".31"/>
<circle cx="180.4" cy="81.6" r=".31"/>
<circle cx="180.4" cy="80.8" r=".31"/>
<circle cx="180.4" cy="84.7" r=".31"/>
<circle cx="181.1" cy="86.3" r=".3"/>
<circle cx="181.1" cy="80" r=".3"/>
<circle cx="181.1" cy="87.9" r=".31"/>
<circle cx="181.1" cy="83.9" r=".3"/>
<circle cx="181.1" cy="88.7" r=".3"/>
<circle cx="181.1" cy="81.6" r=".31"/>
<circle cx="181.1" cy="85.5" r=".3"/>
<circle cx="181.9" cy="82.4" r=".31"/>
<circle cx="181.9" cy="87.1" r=".31"/>
<circle cx="181.9" cy="83.9" r=".3"/>
<circle cx="181.9" cy="80" r=".3"/>
<circle cx="181.9" cy="86.3" r=".3"/>
<circle cx="182.7" cy="83.2" r=".3"/>
<circle cx="172.2" cy="115.8" r=".31"/>
</g>
</svg>
